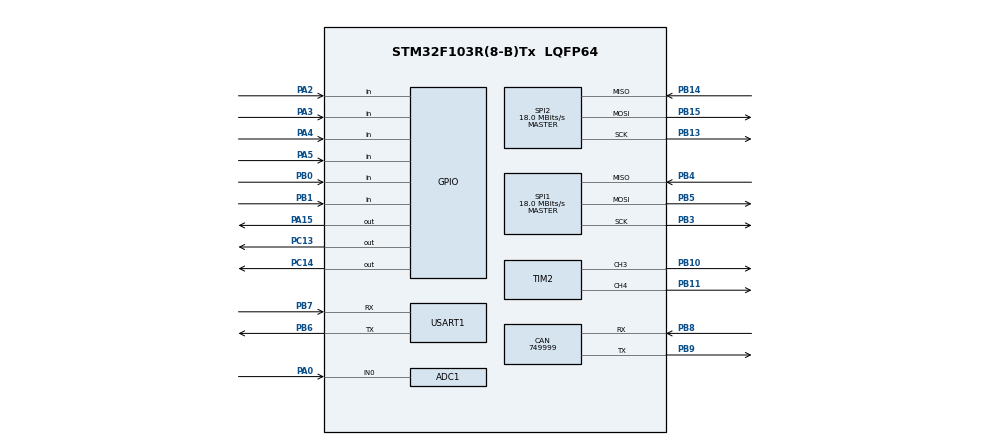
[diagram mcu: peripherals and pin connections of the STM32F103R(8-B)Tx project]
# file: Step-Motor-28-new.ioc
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ADC1.Channel-0\#ChannelRegularConversion=ADC_CHANNEL_0
ADC1.NbrOfConversionFlag=1
ADC1.Rank-0\#ChannelRegularConversion=1
ADC1.SamplingTime-0\#ChannelRegularConversion=ADC_SAMPLETIME_1CYCLE_5
ADC1.master=1
CAN.CalculateBaudRate=749999
CAN.CalculateTimeBit=1333
CAN.CalculateTimeQuantum=444.44444444444446
Mcu.Family=STM32F1
Mcu.Name=STM32F103R(8-B)Tx
Mcu.Package=LQFP64
NVIC.PriorityGroup=NVIC_PRIORITYGROUP_4
PA0-WKUP.Signal=ADCx_IN0
PA13.Mode=Serial_Wire
PA13.Signal=SYS_JTMS-SWDIO
PA14.Mode=Serial_Wire
PA14.Signal=SYS_JTCK-SWCLK
PA15.Signal=GPIO_Output
PA2.Signal=GPIO_Input
PA3.Signal=GPIO_Input
PA4.Signal=GPIO_Input
PA5.Signal=GPIO_Input
PB0.Signal=GPIO_Input
PB1.Signal=GPIO_Input
PB10.Signal=S_TIM2_CH3
PB11.Signal=S_TIM2_CH4
PB13.Mode=Full_Duplex_Master
PB13.Signal=SPI2_SCK
PB14.Mode=Full_Duplex_Master
PB14.Signal=SPI2_MISO
PB15.Mode=Full_Duplex_Master
PB15.Signal=SPI2_MOSI
PB3.Mode=Full_Duplex_Master
PB3.Signal=SPI1_SCK
PB4.Mode=Full_Duplex_Master
PB4.Signal=SPI1_MISO
PB5.Mode=Full_Duplex_Master
PB5.Signal=SPI1_MOSI
PB6.Mode=Asynchronous
PB6.Signal=USART1_TX
PB7.Mode=Asynchronous
PB7.Signal=USART1_RX
PB8.Mode=CAN_Activate
PB8.Signal=CAN_RX
PB9.Mode=CAN_Activate
PB9.Signal=CAN_TX
PC13-TAMPER-RTC.Signal=GPIO_Output
PC14-OSC32_IN.Signal=GPIO_Output
PD0-OSC_IN.Mode=HSE-External-Oscillator
PD0-OSC_IN.Signal=RCC_OSC_IN
PD1-OSC_OUT.Mode=HSE-External-Oscillator
PD1-OSC_OUT.Signal=RCC_OSC_OUT
ProjectManager.HeapSize=0x200
ProjectManager.StackSize=0x400
ProjectManager.TargetToolchain=MDK-ARM V5.32
RCC.ADCPresc=RCC_ADCPCLK2_DIV6
RCC.AHBFreq_Value=72000000
RCC.APB1CLKDivider=RCC_HCLK_DIV2
RCC.APB1Freq_Value=36000000
RCC.APB1TimFreq_Value=72000000
RCC.APB2Freq_Value=72000000
RCC.APB2TimFreq_Value=72000000
RCC.HCLKFreq_Value=72000000
RCC.PLLMUL=RCC_PLL_MUL9
RCC.PLLSourceVirtual=RCC_PLLSOURCE_HSE
RCC.SYSCLKFreq_VALUE=72000000
RCC.SYSCLKSource=RCC_SYSCLKSOURCE_PLLCLK
RCC.USBFreq_Value=72000000
SH.ADCx_IN0.0=ADC1_IN0,IN0
SH.S_TIM2_CH3.0=TIM2_CH3,PWM Generation3 CH3
SH.S_TIM2_CH4.0=TIM2_CH4,PWM Generation4 CH4
SPI1.BaudRatePrescaler=SPI_BAUDRATEPRESCALER_4
SPI1.CalculateBaudRate=18.0 MBits/s
SPI1.Direction=SPI_DIRECTION_2LINES
SPI1.Mode=SPI_MODE_MASTER
SPI1.VirtualType=VM_MASTER
SPI2.BaudRatePrescaler=SPI_BAUDRATEPRESCALER_2
SPI2.CalculateBaudRate=18.0 MBits/s
SPI2.Direction=SPI_DIRECTION_2LINES
SPI2.Mode=SPI_MODE_MASTER
SPI2.VirtualType=VM_MASTER
TIM2.Channel-PWM\ Generation3\ CH3=TIM_CHANNEL_3
TIM2.Channel-PWM\ Generation4\ CH4=TIM_CHANNEL_4
USART1.VirtualMode=VM_ASYNC
board=custom

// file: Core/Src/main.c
#include "main.h"
#include "main_thread.h"

ADC_HandleTypeDef hadc1;

CAN_HandleTypeDef hcan;

SPI_HandleTypeDef hspi1;
SPI_HandleTypeDef hspi2;

TIM_HandleTypeDef htim2;

UART_HandleTypeDef huart1;

void SystemClock_Config(void);
static void MX_GPIO_Init(void);
static void MX_ADC1_Init(void);
static void MX_CAN_Init(void);
static void MX_SPI1_Init(void);
static void MX_SPI2_Init(void);
static void MX_TIM2_Init(void);
static void MX_USART1_UART_Init(void);

int main(void)
{

  HAL_Init();

  SystemClock_Config();

  MX_GPIO_Init();
  MX_ADC1_Init();
  MX_CAN_Init();
  MX_SPI1_Init();
  MX_SPI2_Init();
  MX_TIM2_Init();
  MX_USART1_UART_Init();

  main_thread();
}

void SystemClock_Config(void)
{
  RCC_OscInitTypeDef RCC_OscInitStruct = {0};
  RCC_ClkInitTypeDef RCC_ClkInitStruct = {0};
  RCC_PeriphCLKInitTypeDef PeriphClkInit = {0};

  /** Initializes the RCC Oscillators according to the specified parameters
  * in the RCC_OscInitTypeDef structure.
  */
  RCC_OscInitStruct.OscillatorType = RCC_OSCILLATORTYPE_HSE;
  RCC_OscInitStruct.HSEState = RCC_HSE_ON;
  RCC_OscInitStruct.HSEPredivValue = RCC_HSE_PREDIV_DIV1;
  RCC_OscInitStruct.HSIState = RCC_HSI_ON;
  RCC_OscInitStruct.PLL.PLLState = RCC_PLL_ON;
  RCC_OscInitStruct.PLL.PLLSource = RCC_PLLSOURCE_HSE;
  RCC_OscInitStruct.PLL.PLLMUL = RCC_PLL_MUL8;
  if (HAL_RCC_OscConfig(&RCC_OscInitStruct) != HAL_OK)
  {
    Error_Handler();
  }

  /** Initializes the CPU, AHB and APB buses clocks
  */
  RCC_ClkInitStruct.ClockType = RCC_CLOCKTYPE_HCLK|RCC_CLOCKTYPE_SYSCLK
                              |RCC_CLOCKTYPE_PCLK1|RCC_CLOCKTYPE_PCLK2;
  RCC_ClkInitStruct.SYSCLKSource = RCC_SYSCLKSOURCE_PLLCLK;
  RCC_ClkInitStruct.AHBCLKDivider = RCC_SYSCLK_DIV1;
  RCC_ClkInitStruct.APB1CLKDivider = RCC_HCLK_DIV2;
  RCC_ClkInitStruct.APB2CLKDivider = RCC_HCLK_DIV1;

  if (HAL_RCC_ClockConfig(&RCC_ClkInitStruct, FLASH_LATENCY_3) != HAL_OK) //Flash 等待时间调整为LATENCY_3 防止死机
  {
    Error_Handler();
  }
  PeriphClkInit.PeriphClockSelection = RCC_PERIPHCLK_ADC;
  PeriphClkInit.AdcClockSelection = RCC_ADCPCLK2_DIV6;
  if (HAL_RCCEx_PeriphCLKConfig(&PeriphClkInit) != HAL_OK)
  {
    Error_Handler();
  }
}

static void MX_ADC1_Init(void)
{

  ADC_ChannelConfTypeDef sConfig = {0};

  /** Common config
  */
  hadc1.Instance = ADC1;
  hadc1.Init.ScanConvMode = ADC_SCAN_DISABLE;
  hadc1.Init.ContinuousConvMode = DISABLE;
  hadc1.Init.DiscontinuousConvMode = DISABLE;
  hadc1.Init.ExternalTrigConv = ADC_SOFTWARE_START;
  hadc1.Init.DataAlign = ADC_DATAALIGN_RIGHT;
  hadc1.Init.NbrOfConversion = 1;
  if (HAL_ADC_Init(&hadc1) != HAL_OK)
  {
    Error_Handler();
  }

  /** Configure Regular Channel
  */
  sConfig.Channel = ADC_CHANNEL_0;
  sConfig.Rank = ADC_REGULAR_RANK_1;
  sConfig.SamplingTime = ADC_SAMPLETIME_1CYCLE_5;
  if (HAL_ADC_ConfigChannel(&hadc1, &sConfig) != HAL_OK)
  {
    Error_Handler();
  }

}

static void MX_CAN_Init(void)
{

  hcan.Instance = CAN1;
  hcan.Init.Prescaler = 16;
  hcan.Init.Mode = CAN_MODE_NORMAL;
  hcan.Init.SyncJumpWidth = CAN_SJW_1TQ;
  hcan.Init.TimeSeg1 = CAN_BS1_1TQ;
  hcan.Init.TimeSeg2 = CAN_BS2_1TQ;
  hcan.Init.TimeTriggeredMode = DISABLE;
  hcan.Init.AutoBusOff = DISABLE;
  hcan.Init.AutoWakeUp = DISABLE;
  hcan.Init.AutoRetransmission = DISABLE;
  hcan.Init.ReceiveFifoLocked = DISABLE;
  hcan.Init.TransmitFifoPriority = DISABLE;
  if (HAL_CAN_Init(&hcan) != HAL_OK)
  {
    Error_Handler();
  }

}

static void MX_SPI1_Init(void)
{

  /* SPI1 parameter configuration*/
  hspi1.Instance = SPI1;
  hspi1.Init.Mode = SPI_MODE_MASTER;
  hspi1.Init.Direction = SPI_DIRECTION_2LINES;
  hspi1.Init.DataSize = SPI_DATASIZE_8BIT;
  hspi1.Init.CLKPolarity = SPI_POLARITY_HIGH;
  hspi1.Init.CLKPhase = SPI_PHASE_2EDGE;
  hspi1.Init.NSS = SPI_NSS_SOFT;
  hspi1.Init.BaudRatePrescaler = SPI_BAUDRATEPRESCALER_4;
  hspi1.Init.FirstBit = SPI_FIRSTBIT_MSB;
  hspi1.Init.TIMode = SPI_TIMODE_DISABLE;
  hspi1.Init.CRCCalculation = SPI_CRCCALCULATION_DISABLE;
  hspi1.Init.CRCPolynomial = 10;
  if (HAL_SPI_Init(&hspi1) != HAL_OK)
  {
    Error_Handler();
  }

}

static void MX_SPI2_Init(void)
{

  /* SPI2 parameter configuration*/
  hspi2.Instance = SPI2;
  hspi2.Init.Mode = SPI_MODE_MASTER;
  hspi2.Init.Direction = SPI_DIRECTION_2LINES;
  hspi2.Init.DataSize = SPI_DATASIZE_8BIT;
  hspi2.Init.CLKPolarity = SPI_POLARITY_LOW;
  hspi2.Init.CLKPhase = SPI_PHASE_1EDGE;
  hspi2.Init.NSS = SPI_NSS_SOFT;
  hspi2.Init.BaudRatePrescaler = SPI_BAUDRATEPRESCALER_2;
  hspi2.Init.FirstBit = SPI_FIRSTBIT_MSB;
  hspi2.Init.TIMode = SPI_TIMODE_DISABLE;
  hspi2.Init.CRCCalculation = SPI_CRCCALCULATION_DISABLE;
  hspi2.Init.CRCPolynomial = 10;
  if (HAL_SPI_Init(&hspi2) != HAL_OK)
  {
    Error_Handler();
  }

}

static void MX_TIM2_Init(void)
{

  TIM_MasterConfigTypeDef sMasterConfig = {0};
  TIM_OC_InitTypeDef sConfigOC = {0};

  htim2.Instance = TIM2;
  htim2.Init.Prescaler = 0;
  htim2.Init.CounterMode = TIM_COUNTERMODE_UP;
  htim2.Init.Period = 65535;
  htim2.Init.ClockDivision = TIM_CLOCKDIVISION_DIV1;
  htim2.Init.AutoReloadPreload = TIM_AUTORELOAD_PRELOAD_DISABLE;
  if (HAL_TIM_PWM_Init(&htim2) != HAL_OK)
  {
    Error_Handler();
  }
  sMasterConfig.MasterOutputTrigger = TIM_TRGO_RESET;
  sMasterConfig.MasterSlaveMode = TIM_MASTERSLAVEMODE_DISABLE;
  if (HAL_TIMEx_MasterConfigSynchronization(&htim2, &sMasterConfig) != HAL_OK)
  {
    Error_Handler();
  }
  sConfigOC.OCMode = TIM_OCMODE_PWM1;
  sConfigOC.Pulse = 0;
  sConfigOC.OCPolarity = TIM_OCPOLARITY_HIGH;
  sConfigOC.OCFastMode = TIM_OCFAST_DISABLE;
  if (HAL_TIM_PWM_ConfigChannel(&htim2, &sConfigOC, TIM_CHANNEL_3) != HAL_OK)
  {
    Error_Handler();
  }
  if (HAL_TIM_PWM_ConfigChannel(&htim2, &sConfigOC, TIM_CHANNEL_4) != HAL_OK)
  {
    Error_Handler();
  }
  HAL_TIM_MspPostInit(&htim2);

}

static void MX_USART1_UART_Init(void)
{

  huart1.Instance = USART1;
  huart1.Init.BaudRate = 115200;
  huart1.Init.WordLength = UART_WORDLENGTH_8B;
  huart1.Init.StopBits = UART_STOPBITS_1;
  huart1.Init.Parity = UART_PARITY_NONE;
  huart1.Init.Mode = UART_MODE_TX_RX;
  huart1.Init.HwFlowCtl = UART_HWCONTROL_NONE;
  huart1.Init.OverSampling = UART_OVERSAMPLING_16;
  if (HAL_UART_Init(&huart1) != HAL_OK)
  {
    Error_Handler();
  }

  __HAL_UART_ENABLE_IT(&huart1,UART_IT_RXNE);
  HAL_NVIC_SetPriority(DEBUG_USART_IRQ ,0,1);
  HAL_NVIC_EnableIRQ(DEBUG_USART_IRQ);

}

static void MX_GPIO_Init(void)
{
  GPIO_InitTypeDef GPIO_InitStruct = {0};

  /* GPIO Ports Clock Enable */
  __HAL_RCC_GPIOC_CLK_ENABLE();
  __HAL_RCC_GPIOD_CLK_ENABLE();
  __HAL_RCC_GPIOA_CLK_ENABLE();
  __HAL_RCC_GPIOB_CLK_ENABLE();

  /*Configure GPIO pin Output Level */
  HAL_GPIO_WritePin(GPIOC, GPIO_PIN_13|GPIO_PIN_14, GPIO_PIN_RESET);

  /*Configure GPIO pin Output Level */
  HAL_GPIO_WritePin(GPIOA, GPIO_PIN_15, GPIO_PIN_RESET);
  HAL_GPIO_WritePin(GPIOA, GPIO_PIN_2, GPIO_PIN_RESET);
  HAL_GPIO_WritePin(GPIOA, GPIO_PIN_3, GPIO_PIN_RESET);
  HAL_GPIO_WritePin(GPIOA, GPIO_PIN_4, GPIO_PIN_RESET);
  HAL_GPIO_WritePin(GPIOA, GPIO_PIN_5, GPIO_PIN_RESET);

  HAL_GPIO_WritePin(GPIOB, GPIO_PIN_12, GPIO_PIN_RESET);

  /*Configure GPIO pins : PC13 PC14 */
  GPIO_InitStruct.Pin = GPIO_PIN_13|GPIO_PIN_14;
  GPIO_InitStruct.Mode = GPIO_MODE_OUTPUT_PP;
  GPIO_InitStruct.Pull = GPIO_NOPULL;
  GPIO_InitStruct.Speed = GPIO_SPEED_FREQ_HIGH;
  HAL_GPIO_Init(GPIOC, &GPIO_InitStruct);

  /*Configure GPIO pins : PA2 PA3 PA4 PA5 */
  GPIO_InitStruct.Pin = GPIO_PIN_2|GPIO_PIN_3|GPIO_PIN_4|GPIO_PIN_5;
  GPIO_InitStruct.Mode = GPIO_MODE_OUTPUT_PP;
  GPIO_InitStruct.Pull = GPIO_NOPULL;
  GPIO_InitStruct.Speed = GPIO_SPEED_FREQ_HIGH;
  HAL_GPIO_Init(GPIOA, &GPIO_InitStruct);

  /*Configure GPIO pins : PB0 PB1 */
  GPIO_InitStruct.Pin = GPIO_PIN_0|GPIO_PIN_1;
  GPIO_InitStruct.Mode = GPIO_MODE_INPUT;
  GPIO_InitStruct.Pull = GPIO_NOPULL;
  HAL_GPIO_Init(GPIOB, &GPIO_InitStruct);

  /*Configure GPIO pin : PB12 */
  GPIO_InitStruct.Pin = GPIO_PIN_12;
  GPIO_InitStruct.Mode = GPIO_MODE_OUTPUT_PP;
  GPIO_InitStruct.Pull = GPIO_NOPULL;
  GPIO_InitStruct.Speed = GPIO_SPEED_FREQ_HIGH;
  HAL_GPIO_Init(GPIOB, &GPIO_InitStruct);

  /*Configure GPIO pin : PA15 */
  GPIO_InitStruct.Pin = GPIO_PIN_15 | GPIO_PIN_8;
  GPIO_InitStruct.Mode = GPIO_MODE_OUTPUT_PP;
  GPIO_InitStruct.Pull = GPIO_NOPULL;
  GPIO_InitStruct.Speed = GPIO_SPEED_FREQ_HIGH;
  HAL_GPIO_Init(GPIOA, &GPIO_InitStruct);

}

void Error_Handler(void)
{
  __disable_irq();
  while (1)
  {
  }
}
